VERSION 5.7 ;
  NOWIREEXTENSIONATPIN ON ;
  DIVIDERCHAR "/" ;
  BUSBITCHARS "[]" ;
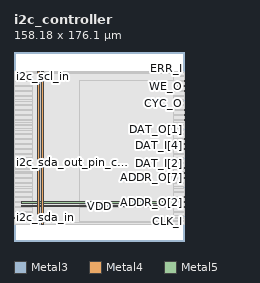
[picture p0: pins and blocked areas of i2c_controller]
MACRO i2c_controller
  CLASS BLOCK ;
  FOREIGN i2c_controller ;
  ORIGIN 0.000 0.000 ;
  SIZE 158.180 BY 176.100 ;
  PIN ACK_I
    DIRECTION INPUT ;
    USE SIGNAL ;
    ANTENNAGATEAREA 0.396000 ;
    PORT
      LAYER Metal3 ;
        RECT 157.620 147.840 158.180 148.400 ;
    END
  END ACK_I
  PIN ADDR_O[0]
    DIRECTION OUTPUT ;
    USE SIGNAL ;
    ANTENNADIFFAREA 0.897600 ;
    PORT
      LAYER Metal3 ;
        RECT 157.620 26.880 158.180 27.440 ;
    END
  END ADDR_O[0]
  PIN ADDR_O[1]
    DIRECTION OUTPUT ;
    USE SIGNAL ;
    ANTENNADIFFAREA 0.897600 ;
    PORT
      LAYER Metal3 ;
        RECT 157.620 31.360 158.180 31.920 ;
    END
  END ADDR_O[1]
  PIN ADDR_O[2]
    DIRECTION OUTPUT ;
    USE SIGNAL ;
    ANTENNADIFFAREA 0.897600 ;
    PORT
      LAYER Metal3 ;
        RECT 157.620 35.840 158.180 36.400 ;
    END
  END ADDR_O[2]
  PIN ADDR_O[3]
    DIRECTION OUTPUT ;
    USE SIGNAL ;
    ANTENNADIFFAREA 0.897600 ;
    PORT
      LAYER Metal3 ;
        RECT 157.620 40.320 158.180 40.880 ;
    END
  END ADDR_O[3]
  PIN ADDR_O[4]
    DIRECTION OUTPUT ;
    USE SIGNAL ;
    ANTENNADIFFAREA 0.897600 ;
    PORT
      LAYER Metal3 ;
        RECT 157.620 44.800 158.180 45.360 ;
    END
  END ADDR_O[4]
  PIN ADDR_O[5]
    DIRECTION OUTPUT ;
    USE SIGNAL ;
    ANTENNADIFFAREA 0.897600 ;
    PORT
      LAYER Metal3 ;
        RECT 157.620 49.280 158.180 49.840 ;
    END
  END ADDR_O[5]
  PIN ADDR_O[6]
    DIRECTION OUTPUT ;
    USE SIGNAL ;
    ANTENNADIFFAREA 0.897600 ;
    PORT
      LAYER Metal3 ;
        RECT 157.620 53.760 158.180 54.320 ;
    END
  END ADDR_O[6]
  PIN ADDR_O[7]
    DIRECTION OUTPUT ;
    USE SIGNAL ;
    ANTENNADIFFAREA 0.897600 ;
    PORT
      LAYER Metal3 ;
        RECT 157.620 58.240 158.180 58.800 ;
    END
  END ADDR_O[7]
  PIN CLK_I
    DIRECTION INPUT ;
    USE SIGNAL ;
    ANTENNAGATEAREA 4.738000 ;
    PORT
      LAYER Metal3 ;
        RECT 157.620 17.920 158.180 18.480 ;
    END
  END CLK_I
  PIN CYC_O
    DIRECTION OUTPUT ;
    USE SIGNAL ;
    ANTENNADIFFAREA 0.897600 ;
    PORT
      LAYER Metal3 ;
        RECT 157.620 134.400 158.180 134.960 ;
    END
  END CYC_O
  PIN DAT_I[0]
    DIRECTION INPUT ;
    USE SIGNAL ;
    ANTENNAGATEAREA 0.396000 ;
    PORT
      LAYER Metal3 ;
        RECT 157.620 62.720 158.180 63.280 ;
    END
  END DAT_I[0]
  PIN DAT_I[1]
    DIRECTION INPUT ;
    USE SIGNAL ;
    ANTENNAGATEAREA 0.396000 ;
    PORT
      LAYER Metal3 ;
        RECT 157.620 67.200 158.180 67.760 ;
    END
  END DAT_I[1]
  PIN DAT_I[2]
    DIRECTION INPUT ;
    USE SIGNAL ;
    ANTENNAGATEAREA 0.396000 ;
    PORT
      LAYER Metal3 ;
        RECT 157.620 71.680 158.180 72.240 ;
    END
  END DAT_I[2]
  PIN DAT_I[3]
    DIRECTION INPUT ;
    USE SIGNAL ;
    ANTENNAGATEAREA 0.396000 ;
    PORT
      LAYER Metal3 ;
        RECT 157.620 76.160 158.180 76.720 ;
    END
  END DAT_I[3]
  PIN DAT_I[4]
    DIRECTION INPUT ;
    USE SIGNAL ;
    ANTENNAGATEAREA 0.396000 ;
    PORT
      LAYER Metal3 ;
        RECT 157.620 80.640 158.180 81.200 ;
    END
  END DAT_I[4]
  PIN DAT_I[5]
    DIRECTION INPUT ;
    USE SIGNAL ;
    ANTENNAGATEAREA 0.396000 ;
    PORT
      LAYER Metal3 ;
        RECT 157.620 85.120 158.180 85.680 ;
    END
  END DAT_I[5]
  PIN DAT_I[6]
    DIRECTION INPUT ;
    USE SIGNAL ;
    ANTENNAGATEAREA 0.396000 ;
    PORT
      LAYER Metal3 ;
        RECT 157.620 89.600 158.180 90.160 ;
    END
  END DAT_I[6]
  PIN DAT_I[7]
    DIRECTION INPUT ;
    USE SIGNAL ;
    ANTENNAGATEAREA 0.396000 ;
    PORT
      LAYER Metal3 ;
        RECT 157.620 94.080 158.180 94.640 ;
    END
  END DAT_I[7]
  PIN DAT_O[0]
    DIRECTION OUTPUT ;
    USE SIGNAL ;
    ANTENNADIFFAREA 0.897600 ;
    PORT
      LAYER Metal3 ;
        RECT 157.620 98.560 158.180 99.120 ;
    END
  END DAT_O[0]
  PIN DAT_O[1]
    DIRECTION OUTPUT ;
    USE SIGNAL ;
    ANTENNADIFFAREA 0.897600 ;
    PORT
      LAYER Metal3 ;
        RECT 157.620 103.040 158.180 103.600 ;
    END
  END DAT_O[1]
  PIN DAT_O[2]
    DIRECTION OUTPUT ;
    USE SIGNAL ;
    ANTENNADIFFAREA 0.897600 ;
    PORT
      LAYER Metal3 ;
        RECT 157.620 107.520 158.180 108.080 ;
    END
  END DAT_O[2]
  PIN DAT_O[3]
    DIRECTION OUTPUT ;
    USE SIGNAL ;
    ANTENNADIFFAREA 0.897600 ;
    PORT
      LAYER Metal3 ;
        RECT 157.620 112.000 158.180 112.560 ;
    END
  END DAT_O[3]
  PIN DAT_O[4]
    DIRECTION OUTPUT ;
    USE SIGNAL ;
    ANTENNADIFFAREA 0.897600 ;
    PORT
      LAYER Metal3 ;
        RECT 157.620 116.480 158.180 117.040 ;
    END
  END DAT_O[4]
  PIN DAT_O[5]
    DIRECTION OUTPUT ;
    USE SIGNAL ;
    ANTENNADIFFAREA 0.897600 ;
    PORT
      LAYER Metal3 ;
        RECT 157.620 120.960 158.180 121.520 ;
    END
  END DAT_O[5]
  PIN DAT_O[6]
    DIRECTION OUTPUT ;
    USE SIGNAL ;
    ANTENNADIFFAREA 0.897600 ;
    PORT
      LAYER Metal3 ;
        RECT 157.620 125.440 158.180 126.000 ;
    END
  END DAT_O[6]
  PIN DAT_O[7]
    DIRECTION OUTPUT ;
    USE SIGNAL ;
    ANTENNADIFFAREA 0.897600 ;
    PORT
      LAYER Metal3 ;
        RECT 157.620 129.920 158.180 130.480 ;
    END
  END DAT_O[7]
  PIN ERR_I
    DIRECTION INPUT ;
    USE SIGNAL ;
    PORT
      LAYER Metal3 ;
        RECT 157.620 152.320 158.180 152.880 ;
    END
  END ERR_I
  PIN RST_I
    DIRECTION INPUT ;
    USE SIGNAL ;
    ANTENNAGATEAREA 0.396000 ;
    PORT
      LAYER Metal3 ;
        RECT 157.620 22.400 158.180 22.960 ;
    END
  END RST_I
  PIN RTY_I
    DIRECTION INPUT ;
    USE SIGNAL ;
    PORT
      LAYER Metal3 ;
        RECT 157.620 156.800 158.180 157.360 ;
    END
  END RTY_I
  PIN STB_O
    DIRECTION OUTPUT ;
    USE SIGNAL ;
    ANTENNADIFFAREA 0.897600 ;
    PORT
      LAYER Metal3 ;
        RECT 157.620 138.880 158.180 139.440 ;
    END
  END STB_O
  PIN VDD
    DIRECTION INOUT ;
    USE POWER ;
    PORT
      LAYER Metal4 ;
        RECT 22.240 15.380 23.840 157.100 ;
    END
    PORT
      LAYER Metal5 ;
        RECT 6.720 31.530 151.200 33.130 ;
    END
  END VDD
  PIN VSS
    DIRECTION INOUT ;
    USE GROUND ;
    PORT
      LAYER Metal4 ;
        RECT 25.540 15.380 27.140 157.100 ;
    END
    PORT
      LAYER Metal5 ;
        RECT 6.720 34.830 151.200 36.430 ;
    END
  END VSS
  PIN WE_O
    DIRECTION OUTPUT ;
    USE SIGNAL ;
    ANTENNADIFFAREA 0.897600 ;
    PORT
      LAYER Metal3 ;
        RECT 157.620 143.360 158.180 143.920 ;
    END
  END WE_O
  PIN i2c_scl_in
    DIRECTION INPUT ;
    USE SIGNAL ;
    ANTENNAGATEAREA 0.396000 ;
    PORT
      LAYER Metal3 ;
        RECT 0.000 152.320 0.560 152.880 ;
    END
  END i2c_scl_in
  PIN i2c_sda_in
    DIRECTION INPUT ;
    USE SIGNAL ;
    ANTENNAGATEAREA 0.396000 ;
    PORT
      LAYER Metal3 ;
        RECT 0.000 21.280 0.560 21.840 ;
    END
  END i2c_sda_in
  PIN i2c_sda_out_pin_ctrl
    DIRECTION OUTPUT ;
    USE SIGNAL ;
    ANTENNADIFFAREA 0.897600 ;
    PORT
      LAYER Metal3 ;
        RECT 0.000 64.960 0.560 65.520 ;
    END
  END i2c_sda_out_pin_ctrl
  PIN i2c_sda_out_pin_ctrl_n
    DIRECTION OUTPUT ;
    USE SIGNAL ;
    ANTENNADIFFAREA 0.897600 ;
    PORT
      LAYER Metal3 ;
        RECT 0.000 108.640 0.560 109.200 ;
    END
  END i2c_sda_out_pin_ctrl_n
  OBS
      LAYER Nwell ;
        RECT 6.290 15.250 151.630 157.230 ;
      LAYER Metal1 ;
        RECT 6.720 15.380 151.200 157.100 ;
      LAYER Metal2 ;
        RECT 7.980 15.490 151.060 156.990 ;
      LAYER Metal3 ;
        RECT 0.560 156.500 157.320 156.940 ;
        RECT 0.560 153.180 158.040 156.500 ;
        RECT 0.860 152.020 157.320 153.180 ;
        RECT 0.560 148.700 158.040 152.020 ;
        RECT 0.560 147.540 157.320 148.700 ;
        RECT 0.560 144.220 158.040 147.540 ;
        RECT 0.560 143.060 157.320 144.220 ;
        RECT 0.560 139.740 158.040 143.060 ;
        RECT 0.560 138.580 157.320 139.740 ;
        RECT 0.560 135.260 158.040 138.580 ;
        RECT 0.560 134.100 157.320 135.260 ;
        RECT 0.560 130.780 158.040 134.100 ;
        RECT 0.560 129.620 157.320 130.780 ;
        RECT 0.560 126.300 158.040 129.620 ;
        RECT 0.560 125.140 157.320 126.300 ;
        RECT 0.560 121.820 158.040 125.140 ;
        RECT 0.560 120.660 157.320 121.820 ;
        RECT 0.560 117.340 158.040 120.660 ;
        RECT 0.560 116.180 157.320 117.340 ;
        RECT 0.560 112.860 158.040 116.180 ;
        RECT 0.560 111.700 157.320 112.860 ;
        RECT 0.560 109.500 158.040 111.700 ;
        RECT 0.860 108.380 158.040 109.500 ;
        RECT 0.860 108.340 157.320 108.380 ;
        RECT 0.560 107.220 157.320 108.340 ;
        RECT 0.560 103.900 158.040 107.220 ;
        RECT 0.560 102.740 157.320 103.900 ;
        RECT 0.560 99.420 158.040 102.740 ;
        RECT 0.560 98.260 157.320 99.420 ;
        RECT 0.560 94.940 158.040 98.260 ;
        RECT 0.560 93.780 157.320 94.940 ;
        RECT 0.560 90.460 158.040 93.780 ;
        RECT 0.560 89.300 157.320 90.460 ;
        RECT 0.560 85.980 158.040 89.300 ;
        RECT 0.560 84.820 157.320 85.980 ;
        RECT 0.560 81.500 158.040 84.820 ;
        RECT 0.560 80.340 157.320 81.500 ;
        RECT 0.560 77.020 158.040 80.340 ;
        RECT 0.560 75.860 157.320 77.020 ;
        RECT 0.560 72.540 158.040 75.860 ;
        RECT 0.560 71.380 157.320 72.540 ;
        RECT 0.560 68.060 158.040 71.380 ;
        RECT 0.560 66.900 157.320 68.060 ;
        RECT 0.560 65.820 158.040 66.900 ;
        RECT 0.860 64.660 158.040 65.820 ;
        RECT 0.560 63.580 158.040 64.660 ;
        RECT 0.560 62.420 157.320 63.580 ;
        RECT 0.560 59.100 158.040 62.420 ;
        RECT 0.560 57.940 157.320 59.100 ;
        RECT 0.560 54.620 158.040 57.940 ;
        RECT 0.560 53.460 157.320 54.620 ;
        RECT 0.560 50.140 158.040 53.460 ;
        RECT 0.560 48.980 157.320 50.140 ;
        RECT 0.560 45.660 158.040 48.980 ;
        RECT 0.560 44.500 157.320 45.660 ;
        RECT 0.560 41.180 158.040 44.500 ;
        RECT 0.560 40.020 157.320 41.180 ;
        RECT 0.560 36.700 158.040 40.020 ;
        RECT 0.560 35.540 157.320 36.700 ;
        RECT 0.560 32.220 158.040 35.540 ;
        RECT 0.560 31.060 157.320 32.220 ;
        RECT 0.560 27.740 158.040 31.060 ;
        RECT 0.560 26.580 157.320 27.740 ;
        RECT 0.560 23.260 158.040 26.580 ;
        RECT 0.560 22.140 157.320 23.260 ;
        RECT 0.860 22.100 157.320 22.140 ;
        RECT 0.860 20.980 158.040 22.100 ;
        RECT 0.560 18.780 158.040 20.980 ;
        RECT 0.560 17.620 157.320 18.780 ;
        RECT 0.560 15.540 158.040 17.620 ;
      LAYER Metal4 ;
        RECT 16.940 16.890 21.940 155.590 ;
        RECT 24.140 16.890 25.240 155.590 ;
        RECT 27.440 16.890 147.700 155.590 ;
      LAYER Metal5 ;
        RECT 61.100 37.030 147.780 149.170 ;
        RECT 61.100 33.730 147.780 34.230 ;
        RECT 61.100 18.230 147.780 30.930 ;
  END
END i2c_controller
END LIBRARY

